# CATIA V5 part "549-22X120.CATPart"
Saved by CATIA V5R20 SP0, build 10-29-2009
Part number: 549-22X120
Definition: NONE
Nomenclature: 549-22X120
Source: Unknown
Description: 549-22X120
Bounding box of the stored display mesh (mm): x 0 to 120, y -12.5 to 12.5, z -12.5 to 12.5
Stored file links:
  C:\Users\Utente\Desktop\IO LAVORO\3D X SITO CF\X SITO\PLASTICA\549\549-22X120.CATPart

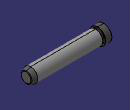
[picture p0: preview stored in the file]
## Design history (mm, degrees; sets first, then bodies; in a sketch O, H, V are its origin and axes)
Body1 "549-22X120" (main body)
  Solid1: solid without history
